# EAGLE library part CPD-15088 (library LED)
CPD-15088A YGD2/A Green 8x8 LED matrix

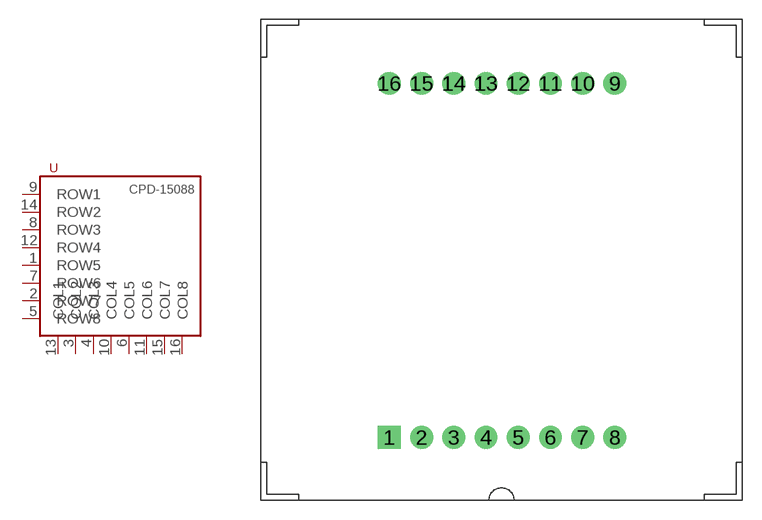
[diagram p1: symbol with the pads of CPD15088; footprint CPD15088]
Designator prefix -

## CPD-15088YGD2/A  [CPD15088]
1  ROW5
2  ROW7
3  COL2
4  COL3
5  ROW8
6  COL5
7  ROW6
8  ROW3
9  ROW1
10  COL4
11  COL6
12  ROW4
13  COL1
14  ROW2
15  COL7
16  COL8

## Footprint CPD15088 (pad centres in mm)
drill 0.5 pad 1.8 square: 1 10.16,-33.02
drill 0.5 pad 1.8: 2 12.7,-33.02; 3 15.24,-33.02; 4 17.78,-33.02; 5 20.32,-33.02; 6 22.86,-33.02; 7 25.4,-33.02; 8 27.94,-33.02; 9 27.94,-5.08; 10 25.4,-5.08; 11 22.86,-5.08; 12 20.32,-5.08; 13 17.78,-5.08; 14 15.24,-5.08; 15 12.7,-5.08; 16 10.16,-5.08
